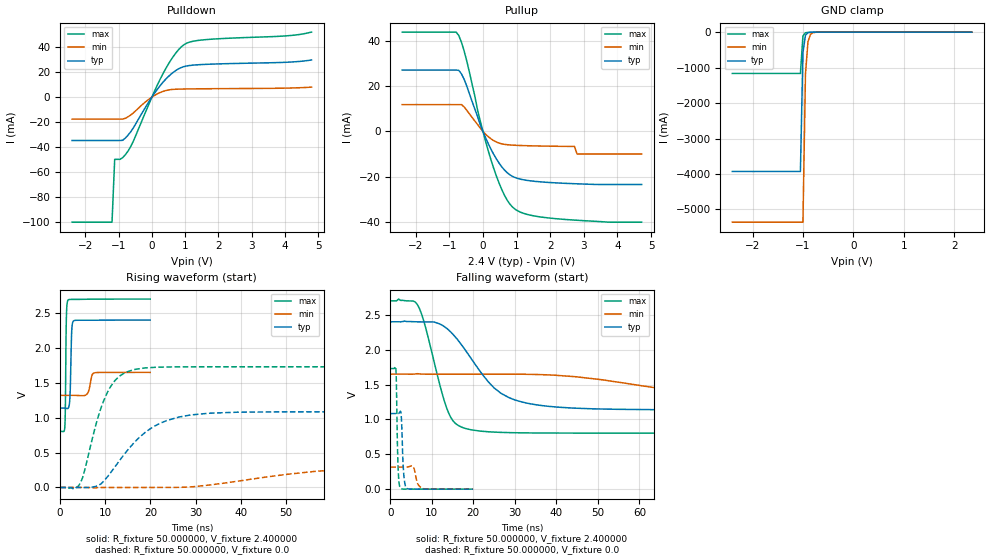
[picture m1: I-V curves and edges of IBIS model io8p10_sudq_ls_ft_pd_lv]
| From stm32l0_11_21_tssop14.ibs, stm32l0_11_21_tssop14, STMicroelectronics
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|   Model io8p10_sudq_ls_ft_pd_lv
[Model]  io8p10_sudq_ls_ft_pd_lv
Model_type I/O
Polarity   Non-Inverting
Enable   Active-Low
Vinl =   0.720000V
Vinh =   1.680000V
Vmeas =  1.200000V
Cref =   50.000000pF
Rref =   100.000000M
Vref =   0.0V
C_comp   2.317700pF   2.286600pF   2.332700pF
[Temperature Range]   25.000000   0.105000k   -40.000000
[Pullup Reference]   2.400000V   1.650000V   2.700000V
[Pulldown Reference]   0.0V   0.0V   0.0V
[POWER Clamp Reference]   2.400000V   1.650000V   2.700000V
[GND Clamp Reference]   0.0V   0.0V   0.0V
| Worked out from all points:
|   slope of the pulldown table from 0 to 0.36 V, typ, clamps not added: 28.4 ohm
|   slope of the pullup table from 0 to 0.36 V, typ, clamps not added: 32.2 ohm
|   GND clamp passes 1 mA (typ) near -0.64 V on its own axis
|   rising waveform, R_fixture 50.000000, V_fixture 2.400000: 20-80 % time 276ps typ, 631ps min, 184ps max; typ from 1.14 V to 2.4 V
|   rising waveform, R_fixture 50.000000, V_fixture 0.0: 20-80 % time 9.37ns typ, 24.8ns min, 4.83ns max; typ from 0 V to 1.08 V
|   falling waveform, R_fixture 50.000000, V_fixture 2.400000: 20-80 % time 10.2ns typ, 27.2ns min, 4.97ns max; typ from 2.4 V to 1.14 V
|   falling waveform, R_fixture 50.000000, V_fixture 0.0: 20-80 % time 455ps typ, 830ps min, 354ps max; typ from 1.08 V to 0 V
[Pulldown]
|Voltage   I(typ)   I(min)   I(max)
-2.4V     -34.71mA   -17.62mA   -100mA
-1.2V     -34.71mA   -17.62mA   -100mA
-1.12V    -34.71mA   -17.62mA   -49.77mA
-960mV    -34.71mA   -17.62mA   -49.77mA
-720mV    -30.52mA   -15.81mA   -43.23mA
-560mV    -24.66mA   -12.69mA   -35.3mA
-80mV     -3.3mA     -1.497mA   -4.982mA
320mV     11.47mA    4.39mA     18.08mA
640mV     19.72mA    6.139mA    32.34mA
960mV     24.33mA    6.432mA    41.77mA
1.52V     26.01mA    6.613mA    45.64mA
4.8V      29.64mA    7.944mA    51.92mA
[Pullup]
|Voltage   I(typ)   I(min)   I(max)
-2.4V     27.2mA     11.88mA    44.01mA
-800mV    27.2mA     11.88mA    44.01mA
-720mV    27.06mA    11.88mA    42.53mA
-560mV    23.11mA    10.87mA    35.65mA
-80mV     3.011mA    1.498mA    4.671mA
320mV     -10.16mA   -4.078mA   -16.34mA
640mV     -17.08mA   -5.718mA   -28.28mA
960mV     -20.45mA   -6.129mA   -34.5mA
2V        -22.64mA   -6.529mA   -38.4mA
2.72V     -23.16mA   -6.64mA    -39.27mA
2.8V      -23.2mA    -10mA      -39.35mA
4.72V     -23.5mA    -10mA      -40.2mA
[GND_clamp]
|Voltage   I(typ)   I(min)   I(max)
-2.4V     -3.929A    -5.359A    -1.166A
-1.05V    -3.929A    -5.359A    -1.166A
-1V       -574.5mA   -5.359A    -109.1mA
-950mV    -90.03mA   -1.192A    -18.56mA
-900mV    -18.42mA   -269.7mA   -9.058mA
-850mV    -6.777mA   -63.61mA   -6.588mA
-800mV    -4.039mA   -16.67mA   -4.867mA
-650mV    -1.055mA   -1.235mA   -1.154mA
2.35V     52.69uA    50.02uA    36.84uA
[POWER_clamp]
|Voltage   I(typ)   I(min)   I(max)
-2.4V     0A         0A         0A
0V        0A         0A         0A
[Ramp]
| variable   typ   min   max
dV/dt_r  0.65004/9.35663n   0.18968/24.75691n   1.03746/4.81881n
dV/dt_f  0.75708/10.16437n   0.19722/27.19091n   1.13771/4.96816n
R_load = 50.000000
[Rising Waveform]
R_fixture= 50.000000
V_fixture= 2.400000
V_fixture_min= 1.650000
V_fixture_max= 2.700000
|time   V(typ)   V(min)   V(max)
0s        1.137V     1.32V      803.3mV
1.041ns   1.137V     1.32V      869.9mV
1.161ns   1.136V     1.32V      1.19V
1.361ns   1.133V     1.32V      2.386V
1.722ns   1.132V     1.32V      2.683V
2.162ns   1.289V     1.32V      2.694V
2.563ns   2.245V     1.32V      2.695V
2.923ns   2.383V     1.32V      2.695V
7.487ns   2.396V     1.64V      2.698V
19.94ns   2.399V     1.649V     2.7V
[Rising Waveform]
R_fixture= 50.000000
V_fixture= 0.0
V_fixture_min= 0.0
V_fixture_max= 0.0
|time   V(typ)   V(min)   V(max)
0s        -472.9nV   -2.959uV   -196.2nV
4.505ns   -898.1uV   97.93uV    64.93mV
8.509ns   31.32mV    -897.5uV   1.032V
11.51ns   240.9mV    -197.5uV   1.477V
14.51ns   501.6mV    -201.3uV   1.648V
19.02ns   798mV      -171uV     1.714V
26.53ns   1.011V     1.557mV    1.728V
39.54ns   1.079V     92.26mV    1.729V
80.58ns   1.083V     302.1mV    1.729V
249.2ns   1.083V     316.1mV    1.729V
[Falling Waveform]
R_fixture= 50.000000
V_fixture= 2.400000
V_fixture_min= 1.650000
V_fixture_max= 2.700000
|time   V(typ)   V(min)   V(max)
0s        2.399V     1.649V     2.7V
6.507ns   2.399V     1.655V     2.648V
8.008ns   2.397V     1.649V     2.422V
12.51ns   2.35V      1.648V     1.367V
14.51ns   2.255V     1.648V     1.035V
21.52ns   1.699V     1.648V     833.1mV
29.03ns   1.301V     1.648V     810mV
44.04ns   1.162V     1.614V     803.7mV
95.6ns    1.137V     1.343V     803.3mV
249.2ns   1.137V     1.32V      803.3mV
[Falling Waveform]
R_fixture= 50.000000
V_fixture= 0.0
V_fixture_min= 0.0
V_fixture_max= 0.0
|time   V(typ)   V(min)   V(max)
0s        1.083V     316.1mV    1.729V
1.321ns   1.083V     316.1mV    1.744V
1.441ns   1.083V     316.1mV    1.585V
1.882ns   1.083V     316.1mV    318.7mV
2.442ns   1.117V     316.1mV    16.15mV
2.683ns   1.013V     316.1mV    5.011mV
3.203ns   246.9mV    315.9mV    1.039mV
3.924ns   13.8mV     315.9mV    1.026mV
7.928ns   341.3uV    7.677mV    865.6uV
19.94ns   -472.9nV   -2.959uV   -196.2nV
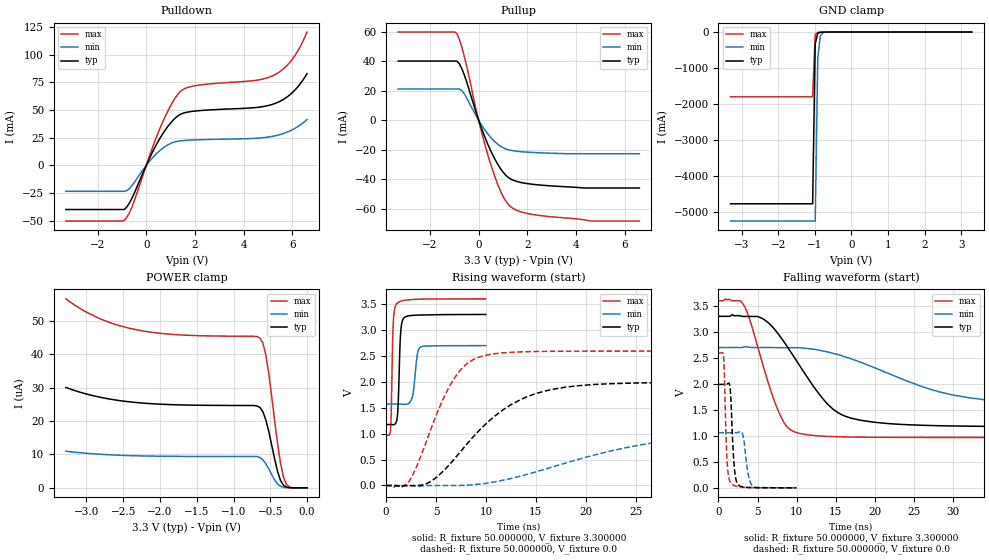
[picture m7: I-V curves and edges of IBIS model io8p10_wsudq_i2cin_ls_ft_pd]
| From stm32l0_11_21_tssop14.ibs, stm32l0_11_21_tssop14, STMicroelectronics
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|   Model io8p10_wsudq_i2cin_ls_ft_pd
[Model]  io8p10_wsudq_i2cin_ls_ft_pd
Model_type I/O
Polarity   Non-Inverting
Enable   Active-Low
Vinl =   0.990000V
Vinh =   2.310000V
Vmeas =  1.650000V
Cref =   50.000000pF
Rref =   100.000000M
Vref =   0.0V
C_comp   3.020400pF   2.988300pF   3.054500pF
[Temperature Range]   25.000000   0.125000k   -40.000000
[Pullup Reference]   3.300000V   2.700000V   3.600000V
[Pulldown Reference]   0.0V   0.0V   0.0V
[POWER Clamp Reference]   3.300000V   2.700000V   3.600000V
[GND Clamp Reference]   0.0V   0.0V   0.0V
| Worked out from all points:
|   slope of the pulldown table from 0 to 0.495 V, typ, clamps not added: 22.6 ohm
|   slope of the pullup table from 0 to 0.495 V, typ, clamps not added: 23.9 ohm
|   GND clamp passes 1 mA (typ) near -0.64 V on its own axis
|   rising waveform, R_fixture 50.000000, V_fixture 3.300000: 20-80 % time 222ps typ, 369ps min, 183ps max; typ from 1.18 V to 3.3 V
|   rising waveform, R_fixture 50.000000, V_fixture 0.0: 20-80 % time 6.53ns typ, 13.6ns min, 3.47ns max; typ from 0 V to 1.99 V
|   falling waveform, R_fixture 50.000000, V_fixture 3.300000: 20-80 % time 5.97ns typ, 12.5ns min, 3.28ns max; typ from 3.3 V to 1.18 V
|   falling waveform, R_fixture 50.000000, V_fixture 0.0: 20-80 % time 405ps typ, 572ps min, 327ps max; typ from 1.99 V to 0 V
[Pulldown]
|Voltage   I(typ)   I(min)   I(max)
-3.3V     -39.83mA   -23.37mA   -50.2mA
-900mV    -39.83mA   -23.37mA   -49.53mA
-600mV    -30.28mA   -18.59mA   -38.45mA
500mV     22.11mA    12.28mA    30.1mA
1V        38.33mA    19.81mA    53.88mA
1.4V      46.1mA     22.18mA    66.72mA
2V        49.07mA    23.02mA    71.93mA
4.4V      52.05mA    24.38mA    76.53mA
5.2V      55.25mA    26.3mA     81.02mA
5.6V      59.18mA    28.57mA    86.57mA
6V        65.79mA    32.24mA    95.97mA
6.6V      82.83mA    41.41mA    120.4mA
[Pullup]
|Voltage   I(typ)   I(min)   I(max)
-3.3V     40.02mA    21.08mA    59.7mA
-900mV    40.02mA    21.08mA    58.93mA
-800mV    38.37mA    21.08mA    55.25mA
-600mV    31.19mA    18.17mA    44.04mA
0V        0A         0A         0A
500mV     -20.88mA   -11.78mA   -30.07mA
900mV     -32.92mA   -17.72mA   -48.15mA
1.3V      -39.75mA   -20.41mA   -58.47mA
1.8V      -42.5mA    -21.48mA   -62.49mA
2.7V      -44.27mA   -22.29mA   -65.04mA
4.6V      -46.01mA   -22.8mA    -68.41mA
6.6V      -46.01mA   -22.8mA    -68.41mA
[GND_clamp]
|Voltage   I(typ)   I(min)   I(max)
-3.3V     -4.766A    -5.244A    -1.797A
-1.06V    -4.766A    -5.244A    -1.797A
-990mV    -326.6mA   -5.244A    -67.91mA
-920mV    -28.93mA   -722.1mA   -10.97mA
-850mV    -6.625mA   -104.2mA   -6.541mA
-780mV    -3.477mA   -17.29mA   -4.218mA
-500mV    -68.5uA    -183uA     -41.48uA
3.28V     73.94uA    88.61uA    51.47uA
[POWER_clamp]
|Voltage   I(typ)   I(min)   I(max)
-3.28V    30.07uA    10.97uA    56.59uA
-2.84V    27.25uA    10.1uA     50.89uA
-2.32V    25.55uA    9.602uA    47.34uA
-640mV    24.06uA    9.099uA    44.84uA
-600mV    22.76uA    8.364uA    43.37uA
-560mV    20.32uA    7.211uA    39.74uA
-520mV    16.86uA    5.675uA    34.14uA
-400mV    4.841uA    1.145uA    13.1uA
-360mV    2.184uA    477.2nA    7.288uA
-320mV    772.4nA    180.3nA    3.213uA
-240mV    60.03nA    0A         295.3nA
0V        0A         0A         0A
[Ramp]
| variable   typ   min   max
dV/dt_r  1.19406/6.52015n   0.62844/13.56230n   1.55520/3.46900n
dV/dt_f  1.27350/5.96154n   0.65370/12.44846n   1.57835/3.27474n
R_load = 50.000000
[Rising Waveform]
R_fixture= 50.000000
V_fixture= 3.300000
V_fixture_min= 2.700000
V_fixture_max= 3.600000
|time   V(typ)   V(min)   V(max)
0s        1.176V     1.571V     968.8mV
440.4ps   1.175V     1.571V     1.074V
700.7ps   1.172V     1.571V     3.072V
1.041ns   1.242V     1.571V     3.501V
1.201ns   1.567V     1.571V     3.529V
1.461ns   2.966V     1.57V      3.553V
1.782ns   3.233V     1.566V     3.57V
2.603ns   3.28V      1.695V     3.585V
3.443ns   3.288V     2.669V     3.594V
9.97ns    3.299V     2.698V     3.599V
[Rising Waveform]
R_fixture= 50.000000
V_fixture= 0.0
V_fixture_min= 0.0
V_fixture_max= 0.0
|time   V(typ)   V(min)   V(max)
0s        408.4nV    -6.246uV   358.7uV
2.302ns   -2.251mV   -1.62mV    82.67mV
4.204ns   48.77mV    -937.9uV   940.5mV
6.507ns   439.3mV    -599.9uV   1.966V
8.008ns   779.8mV    5.187mV    2.334V
9.71ns    1.135V     34.28mV    2.499V
13.91ns   1.695V     203.8mV    2.579V
18.82ns   1.915V     480.3mV    2.591V
30.93ns   1.987V     923mV      2.592V
49.85ns   1.99V      1.06V      2.592V
[Falling Waveform]
R_fixture= 50.000000
V_fixture= 3.300000
V_fixture_min= 2.700000
V_fixture_max= 3.600000
|time   V(typ)   V(min)   V(max)
0s        3.299V     2.698V     3.599V
3.203ns   3.297V     2.705V     3.521V
5.606ns   3.256V     2.699V     2.406V
7.508ns   2.987V     2.697V     1.534V
8.609ns   2.758V     2.696V     1.206V
9.81ns    2.485V     2.695V     1.072V
14.11ns   1.588V     2.608V     988.8mV
18.22ns   1.299V     2.414V     974.8mV
30.23ns   1.19V      1.779V     969.1mV
49.85ns   1.176V     1.571V     968.8mV
[Falling Waveform]
R_fixture= 50.000000
V_fixture= 0.0
V_fixture_min= 0.0
V_fixture_max= 0.0
|time   V(typ)   V(min)   V(max)
0s        1.99V      1.06V      2.592V
640.6ps   1.99V      1.06V      2.54V
1.081ns   1.994V     1.06V      569.7mV
1.522ns   1.854V     1.06V      105.9mV
1.982ns   476.2mV    1.06V      46.98mV
2.482ns   67.94mV    1.065V     21.72mV
3.143ns   17.76mV    1.001V     9.236mV
3.764ns   7.893mV    294.8mV    6.734mV
4.384ns   4.602mV    31.64mV    3.673mV
9.97ns    408.4nV    -6.246uV   358.7uV
